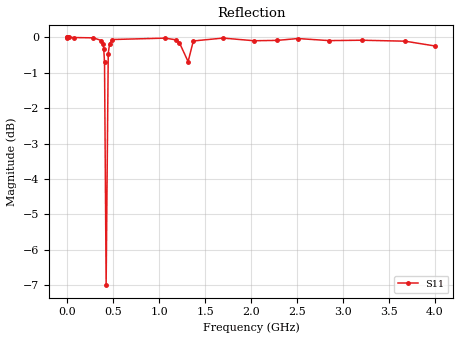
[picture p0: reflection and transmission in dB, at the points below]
#  HZ  Z  MA  R  50.0
! Rohde & Schwarz ZVL
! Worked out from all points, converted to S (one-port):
!   1001 points, 100 kHz to 4 GHz, reference 50 ohm
!   lowest |S11| = -7.0 dB at 423.1 MHz (marker M1), VSWR 2.62, Z = 131 - j3.66 ohm
!   |S11| at or under -10 dB: nowhere
!   S11 on the Smith chart (normalised r, x): 100 kHz: open; 423.1 MHz: 2.61, -0.07; 446.1 MHz: 3, +10; 4 GHz: 72, -5
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100000  4825 56.9
376060.3  5509 162.9
1414214  7397 121.4
5318296  4741 -107.2
2e7  1227 -95.8
7.521206e7  357.7 -88.1
2.828427e8  61.26 -88.0
3.72562e8  20.98 -84.0
3.886931e8  14.53 -81.2
3.970187e8  11.05 -78.3
4.055226e8  7.752 -71.5
4.230808e8  2.614 -1.6
4.461014e8  10.3 74.3
4.605107e8  16.66 80.0
4.907407e8  31.66 84.0
1.063659e9  74.23 -85.6
1.18256e9  36.17 -82.1
1.220757e9  24.37 -77.8
1.314752e9  13.88 56.9
1.371677e9  47.38 74.5
1.695482e9  125.6 -83.2
2.03015e9  31.91 -80.3
2.281134e9  121.5 55.0
2.509397e9  86.38 -81.5
2.849667e9  30.5 -81.1
3.201966e9  140.6 -51.3
3.674883e9  24.88 -81.4
4e9  72.31 -4.0
